VERSION 5.7 ;
BUSBITCHARS "[]" ;
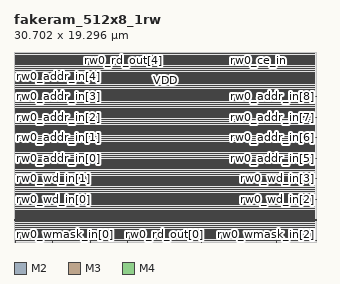
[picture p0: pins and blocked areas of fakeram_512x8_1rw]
MACRO fakeram_512x8_1rw
  FOREIGN fakeram_512x8_1rw 0 0 ;
  SYMMETRY X Y R90 ;
  SIZE 30.702 BY 19.296 ;
  CLASS BLOCK ;
  PIN rw0_wmask_in[0]
    DIRECTION INPUT ;
    USE SIGNAL ;
    SHAPE ABUTMENT ;
    PORT
      LAYER M2 ;
      RECT 0.000 0.138 0.036 0.150 ;
    END
  END rw0_wmask_in[0]
  PIN rw0_wmask_in[1]
    DIRECTION INPUT ;
    USE SIGNAL ;
    SHAPE ABUTMENT ;
    PORT
      LAYER M2 ;
      RECT 0.000 2.226 0.036 2.238 ;
    END
  END rw0_wmask_in[1]
  PIN rw0_wmask_in[2]
    DIRECTION INPUT ;
    USE SIGNAL ;
    SHAPE ABUTMENT ;
    PORT
      LAYER M2 ;
      RECT 30.666 0.138 30.702 0.150 ;
    END
  END rw0_wmask_in[2]
  PIN rw0_wmask_in[3]
    DIRECTION INPUT ;
    USE SIGNAL ;
    SHAPE ABUTMENT ;
    PORT
      LAYER M2 ;
      RECT 30.666 2.226 30.702 2.238 ;
    END
  END rw0_wmask_in[3]
  PIN rw0_wmask_in[4]
    DIRECTION INPUT ;
    USE SIGNAL ;
    SHAPE ABUTMENT ;
    PORT
      LAYER M3 ;
      RECT 0.161 19.254 0.175 19.296 ;
    END
  END rw0_wmask_in[4]
  PIN rw0_wmask_in[5]
    DIRECTION INPUT ;
    USE SIGNAL ;
    SHAPE ABUTMENT ;
    PORT
      LAYER M3 ;
      RECT 2.905 19.254 2.919 19.296 ;
    END
  END rw0_wmask_in[5]
  PIN rw0_wmask_in[6]
    DIRECTION INPUT ;
    USE SIGNAL ;
    SHAPE ABUTMENT ;
    PORT
      LAYER M3 ;
      RECT 5.649 19.254 5.663 19.296 ;
    END
  END rw0_wmask_in[6]
  PIN rw0_wmask_in[7]
    DIRECTION INPUT ;
    USE SIGNAL ;
    SHAPE ABUTMENT ;
    PORT
      LAYER M3 ;
      RECT 8.393 19.254 8.407 19.296 ;
    END
  END rw0_wmask_in[7]
  PIN rw0_wd_in[0]
    DIRECTION INPUT ;
    USE SIGNAL ;
    SHAPE ABUTMENT ;
    PORT
      LAYER M2 ;
      RECT 0.000 4.314 0.036 4.326 ;
    END
  END rw0_wd_in[0]
  PIN rw0_wd_in[1]
    DIRECTION INPUT ;
    USE SIGNAL ;
    SHAPE ABUTMENT ;
    PORT
      LAYER M2 ;
      RECT 0.000 6.402 0.036 6.414 ;
    END
  END rw0_wd_in[1]
  PIN rw0_wd_in[2]
    DIRECTION INPUT ;
    USE SIGNAL ;
    SHAPE ABUTMENT ;
    PORT
      LAYER M2 ;
      RECT 30.666 4.314 30.702 4.326 ;
    END
  END rw0_wd_in[2]
  PIN rw0_wd_in[3]
    DIRECTION INPUT ;
    USE SIGNAL ;
    SHAPE ABUTMENT ;
    PORT
      LAYER M2 ;
      RECT 30.666 6.402 30.702 6.414 ;
    END
  END rw0_wd_in[3]
  PIN rw0_wd_in[4]
    DIRECTION INPUT ;
    USE SIGNAL ;
    SHAPE ABUTMENT ;
    PORT
      LAYER M3 ;
      RECT 0.161 0.000 0.175 0.042 ;
    END
  END rw0_wd_in[4]
  PIN rw0_wd_in[5]
    DIRECTION INPUT ;
    USE SIGNAL ;
    SHAPE ABUTMENT ;
    PORT
      LAYER M3 ;
      RECT 3.941 0.000 3.955 0.042 ;
    END
  END rw0_wd_in[5]
  PIN rw0_wd_in[6]
    DIRECTION INPUT ;
    USE SIGNAL ;
    SHAPE ABUTMENT ;
    PORT
      LAYER M3 ;
      RECT 7.721 0.000 7.735 0.042 ;
    END
  END rw0_wd_in[6]
  PIN rw0_wd_in[7]
    DIRECTION INPUT ;
    USE SIGNAL ;
    SHAPE ABUTMENT ;
    PORT
      LAYER M3 ;
      RECT 11.501 0.000 11.515 0.042 ;
    END
  END rw0_wd_in[7]
  PIN rw0_rd_out[0]
    DIRECTION OUTPUT ;
    USE SIGNAL ;
    SHAPE ABUTMENT ;
    PORT
      LAYER M3 ;
      RECT 15.281 0.000 15.295 0.042 ;
    END
  END rw0_rd_out[0]
  PIN rw0_rd_out[1]
    DIRECTION OUTPUT ;
    USE SIGNAL ;
    SHAPE ABUTMENT ;
    PORT
      LAYER M3 ;
      RECT 19.061 0.000 19.075 0.042 ;
    END
  END rw0_rd_out[1]
  PIN rw0_rd_out[2]
    DIRECTION OUTPUT ;
    USE SIGNAL ;
    SHAPE ABUTMENT ;
    PORT
      LAYER M3 ;
      RECT 22.841 0.000 22.855 0.042 ;
    END
  END rw0_rd_out[2]
  PIN rw0_rd_out[3]
    DIRECTION OUTPUT ;
    USE SIGNAL ;
    SHAPE ABUTMENT ;
    PORT
      LAYER M3 ;
      RECT 26.621 0.000 26.635 0.042 ;
    END
  END rw0_rd_out[3]
  PIN rw0_rd_out[4]
    DIRECTION OUTPUT ;
    USE SIGNAL ;
    SHAPE ABUTMENT ;
    PORT
      LAYER M3 ;
      RECT 11.137 19.254 11.151 19.296 ;
    END
  END rw0_rd_out[4]
  PIN rw0_rd_out[5]
    DIRECTION OUTPUT ;
    USE SIGNAL ;
    SHAPE ABUTMENT ;
    PORT
      LAYER M3 ;
      RECT 13.881 19.254 13.895 19.296 ;
    END
  END rw0_rd_out[5]
  PIN rw0_rd_out[6]
    DIRECTION OUTPUT ;
    USE SIGNAL ;
    SHAPE ABUTMENT ;
    PORT
      LAYER M3 ;
      RECT 16.625 19.254 16.639 19.296 ;
    END
  END rw0_rd_out[6]
  PIN rw0_rd_out[7]
    DIRECTION OUTPUT ;
    USE SIGNAL ;
    SHAPE ABUTMENT ;
    PORT
      LAYER M3 ;
      RECT 19.369 19.254 19.383 19.296 ;
    END
  END rw0_rd_out[7]
  PIN rw0_addr_in[0]
    DIRECTION INPUT ;
    USE SIGNAL ;
    SHAPE ABUTMENT ;
    PORT
      LAYER M2 ;
      RECT 0.000 8.490 0.036 8.502 ;
    END
  END rw0_addr_in[0]
  PIN rw0_addr_in[1]
    DIRECTION INPUT ;
    USE SIGNAL ;
    SHAPE ABUTMENT ;
    PORT
      LAYER M2 ;
      RECT 0.000 10.578 0.036 10.590 ;
    END
  END rw0_addr_in[1]
  PIN rw0_addr_in[2]
    DIRECTION INPUT ;
    USE SIGNAL ;
    SHAPE ABUTMENT ;
    PORT
      LAYER M2 ;
      RECT 0.000 12.666 0.036 12.678 ;
    END
  END rw0_addr_in[2]
  PIN rw0_addr_in[3]
    DIRECTION INPUT ;
    USE SIGNAL ;
    SHAPE ABUTMENT ;
    PORT
      LAYER M2 ;
      RECT 0.000 14.754 0.036 14.766 ;
    END
  END rw0_addr_in[3]
  PIN rw0_addr_in[4]
    DIRECTION INPUT ;
    USE SIGNAL ;
    SHAPE ABUTMENT ;
    PORT
      LAYER M2 ;
      RECT 0.000 16.842 0.036 16.854 ;
    END
  END rw0_addr_in[4]
  PIN rw0_addr_in[5]
    DIRECTION INPUT ;
    USE SIGNAL ;
    SHAPE ABUTMENT ;
    PORT
      LAYER M2 ;
      RECT 30.666 8.490 30.702 8.502 ;
    END
  END rw0_addr_in[5]
  PIN rw0_addr_in[6]
    DIRECTION INPUT ;
    USE SIGNAL ;
    SHAPE ABUTMENT ;
    PORT
      LAYER M2 ;
      RECT 30.666 10.578 30.702 10.590 ;
    END
  END rw0_addr_in[6]
  PIN rw0_addr_in[7]
    DIRECTION INPUT ;
    USE SIGNAL ;
    SHAPE ABUTMENT ;
    PORT
      LAYER M2 ;
      RECT 30.666 12.666 30.702 12.678 ;
    END
  END rw0_addr_in[7]
  PIN rw0_addr_in[8]
    DIRECTION INPUT ;
    USE SIGNAL ;
    SHAPE ABUTMENT ;
    PORT
      LAYER M2 ;
      RECT 30.666 14.754 30.702 14.766 ;
    END
  END rw0_addr_in[8]
  PIN rw0_we_in
    DIRECTION INPUT ;
    USE SIGNAL ;
    SHAPE ABUTMENT ;
    PORT
      LAYER M3 ;
      RECT 22.113 19.254 22.127 19.296 ;
    END
  END rw0_we_in
  PIN rw0_ce_in
    DIRECTION INPUT ;
    USE SIGNAL ;
    SHAPE ABUTMENT ;
    PORT
      LAYER M3 ;
      RECT 24.857 19.254 24.871 19.296 ;
    END
  END rw0_ce_in
  PIN rw0_clk
    DIRECTION INPUT ;
    USE SIGNAL ;
    SHAPE ABUTMENT ;
    PORT
      LAYER M3 ;
      RECT 27.601 19.254 27.615 19.296 ;
    END
  END rw0_clk
  PIN VSS
    DIRECTION INOUT ;
    USE GROUND ;
    PORT
      LAYER M4 ;
      RECT 0.168 0.120 30.534 0.168 ;
      RECT 0.168 0.504 30.534 0.552 ;
      RECT 0.168 0.888 30.534 0.936 ;
      RECT 0.168 1.272 30.534 1.320 ;
      RECT 0.168 1.656 30.534 1.704 ;
      RECT 0.168 2.040 30.534 2.088 ;
      RECT 0.168 2.424 30.534 2.472 ;
      RECT 0.168 2.808 30.534 2.856 ;
      RECT 0.168 3.192 30.534 3.240 ;
      RECT 0.168 3.576 30.534 3.624 ;
      RECT 0.168 3.960 30.534 4.008 ;
      RECT 0.168 4.344 30.534 4.392 ;
      RECT 0.168 4.728 30.534 4.776 ;
      RECT 0.168 5.112 30.534 5.160 ;
      RECT 0.168 5.496 30.534 5.544 ;
      RECT 0.168 5.880 30.534 5.928 ;
      RECT 0.168 6.264 30.534 6.312 ;
      RECT 0.168 6.648 30.534 6.696 ;
      RECT 0.168 7.032 30.534 7.080 ;
      RECT 0.168 7.416 30.534 7.464 ;
      RECT 0.168 7.800 30.534 7.848 ;
      RECT 0.168 8.184 30.534 8.232 ;
      RECT 0.168 8.568 30.534 8.616 ;
      RECT 0.168 8.952 30.534 9.000 ;
      RECT 0.168 9.336 30.534 9.384 ;
      RECT 0.168 9.720 30.534 9.768 ;
      RECT 0.168 10.104 30.534 10.152 ;
      RECT 0.168 10.488 30.534 10.536 ;
      RECT 0.168 10.872 30.534 10.920 ;
      RECT 0.168 11.256 30.534 11.304 ;
      RECT 0.168 11.640 30.534 11.688 ;
      RECT 0.168 12.024 30.534 12.072 ;
      RECT 0.168 12.408 30.534 12.456 ;
      RECT 0.168 12.792 30.534 12.840 ;
      RECT 0.168 13.176 30.534 13.224 ;
      RECT 0.168 13.560 30.534 13.608 ;
      RECT 0.168 13.944 30.534 13.992 ;
      RECT 0.168 14.328 30.534 14.376 ;
      RECT 0.168 14.712 30.534 14.760 ;
      RECT 0.168 15.096 30.534 15.144 ;
      RECT 0.168 15.480 30.534 15.528 ;
      RECT 0.168 15.864 30.534 15.912 ;
      RECT 0.168 16.248 30.534 16.296 ;
      RECT 0.168 16.632 30.534 16.680 ;
      RECT 0.168 17.016 30.534 17.064 ;
      RECT 0.168 17.400 30.534 17.448 ;
      RECT 0.168 17.784 30.534 17.832 ;
      RECT 0.168 18.168 30.534 18.216 ;
      RECT 0.168 18.552 30.534 18.600 ;
      RECT 0.168 18.936 30.534 18.984 ;
    END
  END VSS
  PIN VDD
    DIRECTION INOUT ;
    USE POWER ;
    PORT
      LAYER M4 ;
      RECT 0.168 0.312 30.534 0.360 ;
      RECT 0.168 0.696 30.534 0.744 ;
      RECT 0.168 1.080 30.534 1.128 ;
      RECT 0.168 1.464 30.534 1.512 ;
      RECT 0.168 1.848 30.534 1.896 ;
      RECT 0.168 2.232 30.534 2.280 ;
      RECT 0.168 2.616 30.534 2.664 ;
      RECT 0.168 3.000 30.534 3.048 ;
      RECT 0.168 3.384 30.534 3.432 ;
      RECT 0.168 3.768 30.534 3.816 ;
      RECT 0.168 4.152 30.534 4.200 ;
      RECT 0.168 4.536 30.534 4.584 ;
      RECT 0.168 4.920 30.534 4.968 ;
      RECT 0.168 5.304 30.534 5.352 ;
      RECT 0.168 5.688 30.534 5.736 ;
      RECT 0.168 6.072 30.534 6.120 ;
      RECT 0.168 6.456 30.534 6.504 ;
      RECT 0.168 6.840 30.534 6.888 ;
      RECT 0.168 7.224 30.534 7.272 ;
      RECT 0.168 7.608 30.534 7.656 ;
      RECT 0.168 7.992 30.534 8.040 ;
      RECT 0.168 8.376 30.534 8.424 ;
      RECT 0.168 8.760 30.534 8.808 ;
      RECT 0.168 9.144 30.534 9.192 ;
      RECT 0.168 9.528 30.534 9.576 ;
      RECT 0.168 9.912 30.534 9.960 ;
      RECT 0.168 10.296 30.534 10.344 ;
      RECT 0.168 10.680 30.534 10.728 ;
      RECT 0.168 11.064 30.534 11.112 ;
      RECT 0.168 11.448 30.534 11.496 ;
      RECT 0.168 11.832 30.534 11.880 ;
      RECT 0.168 12.216 30.534 12.264 ;
      RECT 0.168 12.600 30.534 12.648 ;
      RECT 0.168 12.984 30.534 13.032 ;
      RECT 0.168 13.368 30.534 13.416 ;
      RECT 0.168 13.752 30.534 13.800 ;
      RECT 0.168 14.136 30.534 14.184 ;
      RECT 0.168 14.520 30.534 14.568 ;
      RECT 0.168 14.904 30.534 14.952 ;
      RECT 0.168 15.288 30.534 15.336 ;
      RECT 0.168 15.672 30.534 15.720 ;
      RECT 0.168 16.056 30.534 16.104 ;
      RECT 0.168 16.440 30.534 16.488 ;
      RECT 0.168 16.824 30.534 16.872 ;
      RECT 0.168 17.208 30.534 17.256 ;
      RECT 0.168 17.592 30.534 17.640 ;
      RECT 0.168 17.976 30.534 18.024 ;
      RECT 0.168 18.360 30.534 18.408 ;
      RECT 0.168 18.744 30.534 18.792 ;
      RECT 0.168 19.128 30.534 19.176 ;
    END
  END VDD
  OBS
    LAYER M1 ;
    RECT 0 0 30.702 19.296 ;
    LAYER M2 ;
    RECT 0 0 30.702 19.296 ;
    LAYER M3 ;
    RECT 0 0 30.702 19.296 ;
    LAYER M4 ;
    RECT 0 0 30.702 19.296 ;
  END
END fakeram_512x8_1rw

END LIBRARY
